VERSION 5.7 ;
  NOWIREEXTENSIONATPIN ON ;
  DIVIDERCHAR "/" ;
  BUSBITCHARS "[]" ;
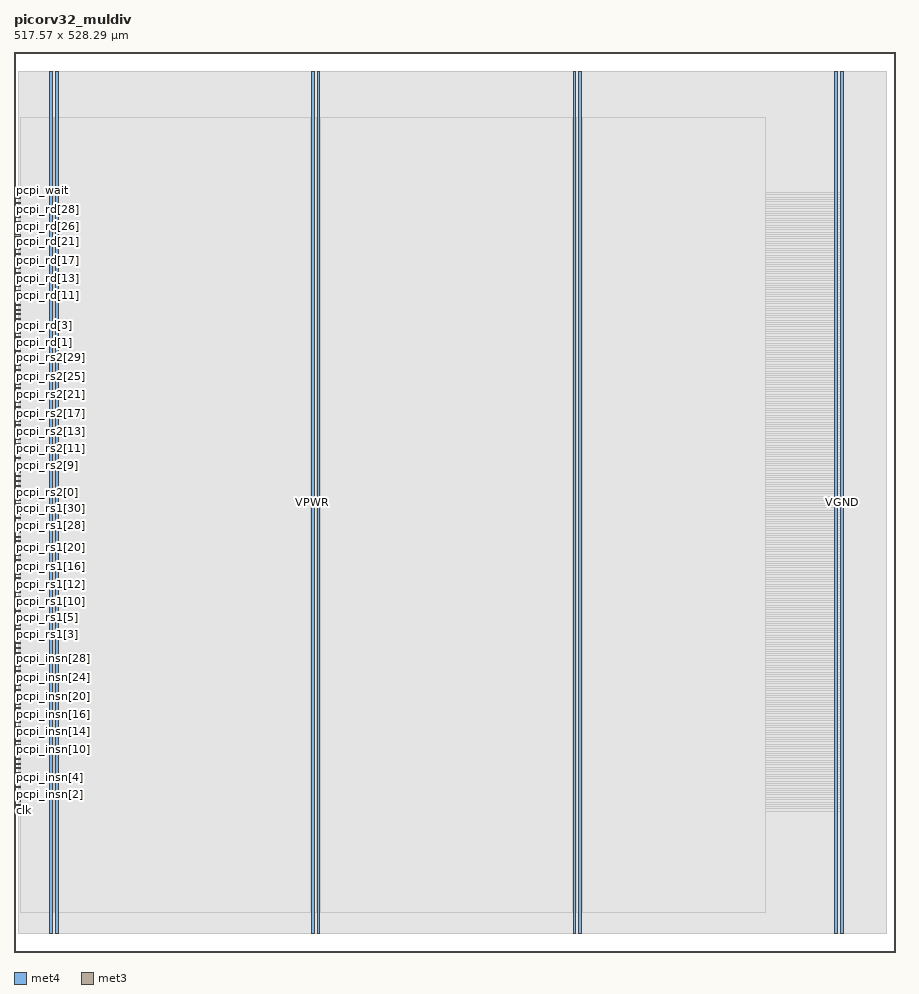
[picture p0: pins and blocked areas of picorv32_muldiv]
MACRO picorv32_muldiv
  CLASS BLOCK ;
  FOREIGN picorv32_muldiv ;
  ORIGIN 0.000 0.000 ;
  SIZE 517.570 BY 528.290 ;
  PIN VGND
    DIRECTION INOUT ;
    USE GROUND ;
    PORT
      LAYER met4 ;
        RECT 24.340 10.640 25.940 517.040 ;
    END
    PORT
      LAYER met4 ;
        RECT 177.940 10.640 179.540 517.040 ;
    END
    PORT
      LAYER met4 ;
        RECT 331.540 10.640 333.140 517.040 ;
    END
    PORT
      LAYER met4 ;
        RECT 485.140 10.640 486.740 517.040 ;
    END
  END VGND
  PIN VPWR
    DIRECTION INOUT ;
    USE POWER ;
    PORT
      LAYER met4 ;
        RECT 21.040 10.640 22.640 517.040 ;
    END
    PORT
      LAYER met4 ;
        RECT 174.640 10.640 176.240 517.040 ;
    END
    PORT
      LAYER met4 ;
        RECT 328.240 10.640 329.840 517.040 ;
    END
    PORT
      LAYER met4 ;
        RECT 481.840 10.640 483.440 517.040 ;
    END
  END VPWR
  PIN clk
    DIRECTION INPUT ;
    USE SIGNAL ;
    ANTENNAGATEAREA 1.286700 ;
    ANTENNADIFFAREA 0.434700 ;
    PORT
      LAYER met3 ;
        RECT 0.000 83.000 4.000 83.600 ;
    END
  END clk
  PIN pcpi_insn[0]
    DIRECTION INPUT ;
    USE SIGNAL ;
    ANTENNAGATEAREA 0.631200 ;
    ANTENNADIFFAREA 0.434700 ;
    PORT
      LAYER met3 ;
        RECT 0.000 91.160 4.000 91.760 ;
    END
  END pcpi_insn[0]
  PIN pcpi_insn[10]
    DIRECTION INPUT ;
    USE SIGNAL ;
    PORT
      LAYER met3 ;
        RECT 0.000 118.360 4.000 118.960 ;
    END
  END pcpi_insn[10]
  PIN pcpi_insn[11]
    DIRECTION INPUT ;
    USE SIGNAL ;
    PORT
      LAYER met3 ;
        RECT 0.000 121.080 4.000 121.680 ;
    END
  END pcpi_insn[11]
  PIN pcpi_insn[12]
    DIRECTION INPUT ;
    USE SIGNAL ;
    ANTENNAGATEAREA 0.560700 ;
    ANTENNADIFFAREA 0.434700 ;
    PORT
      LAYER met3 ;
        RECT 0.000 123.800 4.000 124.400 ;
    END
  END pcpi_insn[12]
  PIN pcpi_insn[13]
    DIRECTION INPUT ;
    USE SIGNAL ;
    ANTENNAGATEAREA 0.560700 ;
    ANTENNADIFFAREA 0.434700 ;
    PORT
      LAYER met3 ;
        RECT 0.000 126.520 4.000 127.120 ;
    END
  END pcpi_insn[13]
  PIN pcpi_insn[14]
    DIRECTION INPUT ;
    USE SIGNAL ;
    ANTENNAGATEAREA 0.560700 ;
    ANTENNADIFFAREA 0.434700 ;
    PORT
      LAYER met3 ;
        RECT 0.000 129.240 4.000 129.840 ;
    END
  END pcpi_insn[14]
  PIN pcpi_insn[15]
    DIRECTION INPUT ;
    USE SIGNAL ;
    PORT
      LAYER met3 ;
        RECT 0.000 131.960 4.000 132.560 ;
    END
  END pcpi_insn[15]
  PIN pcpi_insn[16]
    DIRECTION INPUT ;
    USE SIGNAL ;
    PORT
      LAYER met3 ;
        RECT 0.000 134.680 4.000 135.280 ;
    END
  END pcpi_insn[16]
  PIN pcpi_insn[17]
    DIRECTION INPUT ;
    USE SIGNAL ;
    PORT
      LAYER met3 ;
        RECT 0.000 137.400 4.000 138.000 ;
    END
  END pcpi_insn[17]
  PIN pcpi_insn[18]
    DIRECTION INPUT ;
    USE SIGNAL ;
    PORT
      LAYER met3 ;
        RECT 0.000 140.120 4.000 140.720 ;
    END
  END pcpi_insn[18]
  PIN pcpi_insn[19]
    DIRECTION INPUT ;
    USE SIGNAL ;
    PORT
      LAYER met3 ;
        RECT 0.000 142.840 4.000 143.440 ;
    END
  END pcpi_insn[19]
  PIN pcpi_insn[1]
    DIRECTION INPUT ;
    USE SIGNAL ;
    ANTENNAGATEAREA 0.631200 ;
    ANTENNADIFFAREA 0.434700 ;
    PORT
      LAYER met3 ;
        RECT 0.000 93.880 4.000 94.480 ;
    END
  END pcpi_insn[1]
  PIN pcpi_insn[20]
    DIRECTION INPUT ;
    USE SIGNAL ;
    PORT
      LAYER met3 ;
        RECT 0.000 145.560 4.000 146.160 ;
    END
  END pcpi_insn[20]
  PIN pcpi_insn[21]
    DIRECTION INPUT ;
    USE SIGNAL ;
    PORT
      LAYER met3 ;
        RECT 0.000 148.280 4.000 148.880 ;
    END
  END pcpi_insn[21]
  PIN pcpi_insn[22]
    DIRECTION INPUT ;
    USE SIGNAL ;
    PORT
      LAYER met3 ;
        RECT 0.000 151.000 4.000 151.600 ;
    END
  END pcpi_insn[22]
  PIN pcpi_insn[23]
    DIRECTION INPUT ;
    USE SIGNAL ;
    PORT
      LAYER met3 ;
        RECT 0.000 153.720 4.000 154.320 ;
    END
  END pcpi_insn[23]
  PIN pcpi_insn[24]
    DIRECTION INPUT ;
    USE SIGNAL ;
    PORT
      LAYER met3 ;
        RECT 0.000 156.440 4.000 157.040 ;
    END
  END pcpi_insn[24]
  PIN pcpi_insn[25]
    DIRECTION INPUT ;
    USE SIGNAL ;
    ANTENNAGATEAREA 0.631200 ;
    ANTENNADIFFAREA 0.434700 ;
    PORT
      LAYER met3 ;
        RECT 0.000 159.160 4.000 159.760 ;
    END
  END pcpi_insn[25]
  PIN pcpi_insn[26]
    DIRECTION INPUT ;
    USE SIGNAL ;
    ANTENNAGATEAREA 0.631200 ;
    ANTENNADIFFAREA 0.434700 ;
    PORT
      LAYER met3 ;
        RECT 0.000 161.880 4.000 162.480 ;
    END
  END pcpi_insn[26]
  PIN pcpi_insn[27]
    DIRECTION INPUT ;
    USE SIGNAL ;
    ANTENNAGATEAREA 0.631200 ;
    ANTENNADIFFAREA 0.434700 ;
    PORT
      LAYER met3 ;
        RECT 0.000 164.600 4.000 165.200 ;
    END
  END pcpi_insn[27]
  PIN pcpi_insn[28]
    DIRECTION INPUT ;
    USE SIGNAL ;
    ANTENNAGATEAREA 0.631200 ;
    ANTENNADIFFAREA 0.434700 ;
    PORT
      LAYER met3 ;
        RECT 0.000 167.320 4.000 167.920 ;
    END
  END pcpi_insn[28]
  PIN pcpi_insn[29]
    DIRECTION INPUT ;
    USE SIGNAL ;
    ANTENNAGATEAREA 0.631200 ;
    ANTENNADIFFAREA 0.434700 ;
    PORT
      LAYER met3 ;
        RECT 0.000 170.040 4.000 170.640 ;
    END
  END pcpi_insn[29]
  PIN pcpi_insn[2]
    DIRECTION INPUT ;
    USE SIGNAL ;
    ANTENNAGATEAREA 0.631200 ;
    ANTENNADIFFAREA 0.434700 ;
    PORT
      LAYER met3 ;
        RECT 0.000 96.600 4.000 97.200 ;
    END
  END pcpi_insn[2]
  PIN pcpi_insn[30]
    DIRECTION INPUT ;
    USE SIGNAL ;
    ANTENNAGATEAREA 0.631200 ;
    ANTENNADIFFAREA 0.434700 ;
    PORT
      LAYER met3 ;
        RECT 0.000 172.760 4.000 173.360 ;
    END
  END pcpi_insn[30]
  PIN pcpi_insn[31]
    DIRECTION INPUT ;
    USE SIGNAL ;
    ANTENNAGATEAREA 0.631200 ;
    ANTENNADIFFAREA 0.434700 ;
    PORT
      LAYER met3 ;
        RECT 0.000 175.480 4.000 176.080 ;
    END
  END pcpi_insn[31]
  PIN pcpi_insn[3]
    DIRECTION INPUT ;
    USE SIGNAL ;
    ANTENNAGATEAREA 0.631200 ;
    ANTENNADIFFAREA 0.434700 ;
    PORT
      LAYER met3 ;
        RECT 0.000 99.320 4.000 99.920 ;
    END
  END pcpi_insn[3]
  PIN pcpi_insn[4]
    DIRECTION INPUT ;
    USE SIGNAL ;
    ANTENNAGATEAREA 0.631200 ;
    ANTENNADIFFAREA 0.434700 ;
    PORT
      LAYER met3 ;
        RECT 0.000 102.040 4.000 102.640 ;
    END
  END pcpi_insn[4]
  PIN pcpi_insn[5]
    DIRECTION INPUT ;
    USE SIGNAL ;
    ANTENNAGATEAREA 0.631200 ;
    ANTENNADIFFAREA 0.434700 ;
    PORT
      LAYER met3 ;
        RECT 0.000 104.760 4.000 105.360 ;
    END
  END pcpi_insn[5]
  PIN pcpi_insn[6]
    DIRECTION INPUT ;
    USE SIGNAL ;
    ANTENNAGATEAREA 0.560700 ;
    ANTENNADIFFAREA 0.434700 ;
    PORT
      LAYER met3 ;
        RECT 0.000 107.480 4.000 108.080 ;
    END
  END pcpi_insn[6]
  PIN pcpi_insn[7]
    DIRECTION INPUT ;
    USE SIGNAL ;
    PORT
      LAYER met3 ;
        RECT 0.000 110.200 4.000 110.800 ;
    END
  END pcpi_insn[7]
  PIN pcpi_insn[8]
    DIRECTION INPUT ;
    USE SIGNAL ;
    PORT
      LAYER met3 ;
        RECT 0.000 112.920 4.000 113.520 ;
    END
  END pcpi_insn[8]
  PIN pcpi_insn[9]
    DIRECTION INPUT ;
    USE SIGNAL ;
    PORT
      LAYER met3 ;
        RECT 0.000 115.640 4.000 116.240 ;
    END
  END pcpi_insn[9]
  PIN pcpi_rd[0]
    DIRECTION OUTPUT ;
    USE SIGNAL ;
    ANTENNAGATEAREA 0.434700 ;
    ANTENNADIFFAREA 0.880200 ;
    PORT
      LAYER met3 ;
        RECT 0.000 355.000 4.000 355.600 ;
    END
  END pcpi_rd[0]
  PIN pcpi_rd[10]
    DIRECTION OUTPUT ;
    USE SIGNAL ;
    ANTENNAGATEAREA 0.434700 ;
    ANTENNADIFFAREA 0.880200 ;
    PORT
      LAYER met3 ;
        RECT 0.000 382.200 4.000 382.800 ;
    END
  END pcpi_rd[10]
  PIN pcpi_rd[11]
    DIRECTION OUTPUT ;
    USE SIGNAL ;
    ANTENNAGATEAREA 0.434700 ;
    ANTENNADIFFAREA 0.880200 ;
    PORT
      LAYER met3 ;
        RECT 0.000 384.920 4.000 385.520 ;
    END
  END pcpi_rd[11]
  PIN pcpi_rd[12]
    DIRECTION OUTPUT ;
    USE SIGNAL ;
    ANTENNAGATEAREA 0.434700 ;
    ANTENNADIFFAREA 0.880200 ;
    PORT
      LAYER met3 ;
        RECT 0.000 387.640 4.000 388.240 ;
    END
  END pcpi_rd[12]
  PIN pcpi_rd[13]
    DIRECTION OUTPUT ;
    USE SIGNAL ;
    ANTENNAGATEAREA 0.434700 ;
    ANTENNADIFFAREA 0.880200 ;
    PORT
      LAYER met3 ;
        RECT 0.000 390.360 4.000 390.960 ;
    END
  END pcpi_rd[13]
  PIN pcpi_rd[14]
    DIRECTION OUTPUT ;
    USE SIGNAL ;
    ANTENNAGATEAREA 0.434700 ;
    ANTENNADIFFAREA 0.880200 ;
    PORT
      LAYER met3 ;
        RECT 0.000 393.080 4.000 393.680 ;
    END
  END pcpi_rd[14]
  PIN pcpi_rd[15]
    DIRECTION OUTPUT ;
    USE SIGNAL ;
    ANTENNAGATEAREA 0.434700 ;
    ANTENNADIFFAREA 0.880200 ;
    PORT
      LAYER met3 ;
        RECT 0.000 395.800 4.000 396.400 ;
    END
  END pcpi_rd[15]
  PIN pcpi_rd[16]
    DIRECTION OUTPUT ;
    USE SIGNAL ;
    ANTENNAGATEAREA 0.434700 ;
    ANTENNADIFFAREA 0.880200 ;
    PORT
      LAYER met3 ;
        RECT 0.000 398.520 4.000 399.120 ;
    END
  END pcpi_rd[16]
  PIN pcpi_rd[17]
    DIRECTION OUTPUT ;
    USE SIGNAL ;
    ANTENNAGATEAREA 0.434700 ;
    ANTENNADIFFAREA 0.880200 ;
    PORT
      LAYER met3 ;
        RECT 0.000 401.240 4.000 401.840 ;
    END
  END pcpi_rd[17]
  PIN pcpi_rd[18]
    DIRECTION OUTPUT ;
    USE SIGNAL ;
    ANTENNAGATEAREA 0.434700 ;
    ANTENNADIFFAREA 0.880200 ;
    PORT
      LAYER met3 ;
        RECT 0.000 403.960 4.000 404.560 ;
    END
  END pcpi_rd[18]
  PIN pcpi_rd[19]
    DIRECTION OUTPUT ;
    USE SIGNAL ;
    ANTENNAGATEAREA 0.434700 ;
    ANTENNADIFFAREA 0.880200 ;
    PORT
      LAYER met3 ;
        RECT 0.000 406.680 4.000 407.280 ;
    END
  END pcpi_rd[19]
  PIN pcpi_rd[1]
    DIRECTION OUTPUT ;
    USE SIGNAL ;
    ANTENNAGATEAREA 0.434700 ;
    ANTENNADIFFAREA 0.880200 ;
    PORT
      LAYER met3 ;
        RECT 0.000 357.720 4.000 358.320 ;
    END
  END pcpi_rd[1]
  PIN pcpi_rd[20]
    DIRECTION OUTPUT ;
    USE SIGNAL ;
    ANTENNAGATEAREA 0.434700 ;
    ANTENNADIFFAREA 0.880200 ;
    PORT
      LAYER met3 ;
        RECT 0.000 409.400 4.000 410.000 ;
    END
  END pcpi_rd[20]
  PIN pcpi_rd[21]
    DIRECTION OUTPUT ;
    USE SIGNAL ;
    ANTENNAGATEAREA 0.434700 ;
    ANTENNADIFFAREA 0.880200 ;
    PORT
      LAYER met3 ;
        RECT 0.000 412.120 4.000 412.720 ;
    END
  END pcpi_rd[21]
  PIN pcpi_rd[22]
    DIRECTION OUTPUT ;
    USE SIGNAL ;
    ANTENNAGATEAREA 0.434700 ;
    ANTENNADIFFAREA 0.880200 ;
    PORT
      LAYER met3 ;
        RECT 0.000 414.840 4.000 415.440 ;
    END
  END pcpi_rd[22]
  PIN pcpi_rd[23]
    DIRECTION OUTPUT ;
    USE SIGNAL ;
    ANTENNAGATEAREA 0.434700 ;
    ANTENNADIFFAREA 0.880200 ;
    PORT
      LAYER met3 ;
        RECT 0.000 417.560 4.000 418.160 ;
    END
  END pcpi_rd[23]
  PIN pcpi_rd[24]
    DIRECTION OUTPUT ;
    USE SIGNAL ;
    ANTENNAGATEAREA 0.434700 ;
    ANTENNADIFFAREA 0.880200 ;
    PORT
      LAYER met3 ;
        RECT 0.000 420.280 4.000 420.880 ;
    END
  END pcpi_rd[24]
  PIN pcpi_rd[25]
    DIRECTION OUTPUT ;
    USE SIGNAL ;
    ANTENNAGATEAREA 0.434700 ;
    ANTENNADIFFAREA 0.880200 ;
    PORT
      LAYER met3 ;
        RECT 0.000 423.000 4.000 423.600 ;
    END
  END pcpi_rd[25]
  PIN pcpi_rd[26]
    DIRECTION OUTPUT ;
    USE SIGNAL ;
    ANTENNAGATEAREA 0.434700 ;
    ANTENNADIFFAREA 0.880200 ;
    PORT
      LAYER met3 ;
        RECT 0.000 425.720 4.000 426.320 ;
    END
  END pcpi_rd[26]
  PIN pcpi_rd[27]
    DIRECTION OUTPUT ;
    USE SIGNAL ;
    ANTENNAGATEAREA 0.434700 ;
    ANTENNADIFFAREA 0.880200 ;
    PORT
      LAYER met3 ;
        RECT 0.000 428.440 4.000 429.040 ;
    END
  END pcpi_rd[27]
  PIN pcpi_rd[28]
    DIRECTION OUTPUT ;
    USE SIGNAL ;
    ANTENNAGATEAREA 0.434700 ;
    ANTENNADIFFAREA 0.880200 ;
    PORT
      LAYER met3 ;
        RECT 0.000 431.160 4.000 431.760 ;
    END
  END pcpi_rd[28]
  PIN pcpi_rd[29]
    DIRECTION OUTPUT ;
    USE SIGNAL ;
    ANTENNAGATEAREA 0.434700 ;
    ANTENNADIFFAREA 0.880200 ;
    PORT
      LAYER met3 ;
        RECT 0.000 433.880 4.000 434.480 ;
    END
  END pcpi_rd[29]
  PIN pcpi_rd[2]
    DIRECTION OUTPUT ;
    USE SIGNAL ;
    ANTENNAGATEAREA 0.434700 ;
    ANTENNADIFFAREA 0.880200 ;
    PORT
      LAYER met3 ;
        RECT 0.000 360.440 4.000 361.040 ;
    END
  END pcpi_rd[2]
  PIN pcpi_rd[30]
    DIRECTION OUTPUT ;
    USE SIGNAL ;
    ANTENNAGATEAREA 0.434700 ;
    ANTENNADIFFAREA 0.880200 ;
    PORT
      LAYER met3 ;
        RECT 0.000 436.600 4.000 437.200 ;
    END
  END pcpi_rd[30]
  PIN pcpi_rd[31]
    DIRECTION OUTPUT ;
    USE SIGNAL ;
    ANTENNAGATEAREA 0.434700 ;
    ANTENNADIFFAREA 0.880200 ;
    PORT
      LAYER met3 ;
        RECT 0.000 439.320 4.000 439.920 ;
    END
  END pcpi_rd[31]
  PIN pcpi_rd[3]
    DIRECTION OUTPUT ;
    USE SIGNAL ;
    ANTENNAGATEAREA 0.434700 ;
    ANTENNADIFFAREA 0.880200 ;
    PORT
      LAYER met3 ;
        RECT 0.000 363.160 4.000 363.760 ;
    END
  END pcpi_rd[3]
  PIN pcpi_rd[4]
    DIRECTION OUTPUT ;
    USE SIGNAL ;
    ANTENNAGATEAREA 0.434700 ;
    ANTENNADIFFAREA 0.880200 ;
    PORT
      LAYER met3 ;
        RECT 0.000 365.880 4.000 366.480 ;
    END
  END pcpi_rd[4]
  PIN pcpi_rd[5]
    DIRECTION OUTPUT ;
    USE SIGNAL ;
    ANTENNAGATEAREA 0.434700 ;
    ANTENNADIFFAREA 0.880200 ;
    PORT
      LAYER met3 ;
        RECT 0.000 368.600 4.000 369.200 ;
    END
  END pcpi_rd[5]
  PIN pcpi_rd[6]
    DIRECTION OUTPUT ;
    USE SIGNAL ;
    ANTENNAGATEAREA 0.434700 ;
    ANTENNADIFFAREA 0.880200 ;
    PORT
      LAYER met3 ;
        RECT 0.000 371.320 4.000 371.920 ;
    END
  END pcpi_rd[6]
  PIN pcpi_rd[7]
    DIRECTION OUTPUT ;
    USE SIGNAL ;
    ANTENNAGATEAREA 0.434700 ;
    ANTENNADIFFAREA 0.880200 ;
    PORT
      LAYER met3 ;
        RECT 0.000 374.040 4.000 374.640 ;
    END
  END pcpi_rd[7]
  PIN pcpi_rd[8]
    DIRECTION OUTPUT ;
    USE SIGNAL ;
    ANTENNAGATEAREA 0.434700 ;
    ANTENNADIFFAREA 0.880200 ;
    PORT
      LAYER met3 ;
        RECT 0.000 376.760 4.000 377.360 ;
    END
  END pcpi_rd[8]
  PIN pcpi_rd[9]
    DIRECTION OUTPUT ;
    USE SIGNAL ;
    ANTENNAGATEAREA 0.434700 ;
    ANTENNADIFFAREA 0.880200 ;
    PORT
      LAYER met3 ;
        RECT 0.000 379.480 4.000 380.080 ;
    END
  END pcpi_rd[9]
  PIN pcpi_ready
    DIRECTION OUTPUT ;
    USE SIGNAL ;
    ANTENNAGATEAREA 0.434700 ;
    ANTENNADIFFAREA 0.880200 ;
    PORT
      LAYER met3 ;
        RECT 0.000 444.760 4.000 445.360 ;
    END
  END pcpi_ready
  PIN pcpi_rs1[0]
    DIRECTION INPUT ;
    USE SIGNAL ;
    ANTENNAGATEAREA 0.560700 ;
    ANTENNADIFFAREA 0.434700 ;
    PORT
      LAYER met3 ;
        RECT 0.000 178.200 4.000 178.800 ;
    END
  END pcpi_rs1[0]
  PIN pcpi_rs1[10]
    DIRECTION INPUT ;
    USE SIGNAL ;
    ANTENNAGATEAREA 0.560700 ;
    ANTENNADIFFAREA 0.434700 ;
    PORT
      LAYER met3 ;
        RECT 0.000 205.400 4.000 206.000 ;
    END
  END pcpi_rs1[10]
  PIN pcpi_rs1[11]
    DIRECTION INPUT ;
    USE SIGNAL ;
    ANTENNAGATEAREA 0.560700 ;
    ANTENNADIFFAREA 0.434700 ;
    PORT
      LAYER met3 ;
        RECT 0.000 208.120 4.000 208.720 ;
    END
  END pcpi_rs1[11]
  PIN pcpi_rs1[12]
    DIRECTION INPUT ;
    USE SIGNAL ;
    ANTENNAGATEAREA 0.560700 ;
    ANTENNADIFFAREA 0.434700 ;
    PORT
      LAYER met3 ;
        RECT 0.000 210.840 4.000 211.440 ;
    END
  END pcpi_rs1[12]
  PIN pcpi_rs1[13]
    DIRECTION INPUT ;
    USE SIGNAL ;
    ANTENNAGATEAREA 0.560700 ;
    ANTENNADIFFAREA 0.434700 ;
    PORT
      LAYER met3 ;
        RECT 0.000 213.560 4.000 214.160 ;
    END
  END pcpi_rs1[13]
  PIN pcpi_rs1[14]
    DIRECTION INPUT ;
    USE SIGNAL ;
    ANTENNAGATEAREA 0.560700 ;
    ANTENNADIFFAREA 0.434700 ;
    PORT
      LAYER met3 ;
        RECT 0.000 216.280 4.000 216.880 ;
    END
  END pcpi_rs1[14]
  PIN pcpi_rs1[15]
    DIRECTION INPUT ;
    USE SIGNAL ;
    ANTENNAGATEAREA 0.560700 ;
    ANTENNADIFFAREA 0.434700 ;
    PORT
      LAYER met3 ;
        RECT 0.000 219.000 4.000 219.600 ;
    END
  END pcpi_rs1[15]
  PIN pcpi_rs1[16]
    DIRECTION INPUT ;
    USE SIGNAL ;
    ANTENNAGATEAREA 0.560700 ;
    ANTENNADIFFAREA 0.434700 ;
    PORT
      LAYER met3 ;
        RECT 0.000 221.720 4.000 222.320 ;
    END
  END pcpi_rs1[16]
  PIN pcpi_rs1[17]
    DIRECTION INPUT ;
    USE SIGNAL ;
    ANTENNAGATEAREA 0.560700 ;
    ANTENNADIFFAREA 0.434700 ;
    PORT
      LAYER met3 ;
        RECT 0.000 224.440 4.000 225.040 ;
    END
  END pcpi_rs1[17]
  PIN pcpi_rs1[18]
    DIRECTION INPUT ;
    USE SIGNAL ;
    ANTENNAGATEAREA 0.560700 ;
    ANTENNADIFFAREA 0.434700 ;
    PORT
      LAYER met3 ;
        RECT 0.000 227.160 4.000 227.760 ;
    END
  END pcpi_rs1[18]
  PIN pcpi_rs1[19]
    DIRECTION INPUT ;
    USE SIGNAL ;
    ANTENNAGATEAREA 0.560700 ;
    ANTENNADIFFAREA 0.434700 ;
    PORT
      LAYER met3 ;
        RECT 0.000 229.880 4.000 230.480 ;
    END
  END pcpi_rs1[19]
  PIN pcpi_rs1[1]
    DIRECTION INPUT ;
    USE SIGNAL ;
    ANTENNAGATEAREA 0.560700 ;
    ANTENNADIFFAREA 0.434700 ;
    PORT
      LAYER met3 ;
        RECT 0.000 180.920 4.000 181.520 ;
    END
  END pcpi_rs1[1]
  PIN pcpi_rs1[20]
    DIRECTION INPUT ;
    USE SIGNAL ;
    ANTENNAGATEAREA 0.560700 ;
    ANTENNADIFFAREA 0.434700 ;
    PORT
      LAYER met3 ;
        RECT 0.000 232.600 4.000 233.200 ;
    END
  END pcpi_rs1[20]
  PIN pcpi_rs1[21]
    DIRECTION INPUT ;
    USE SIGNAL ;
    ANTENNAGATEAREA 0.560700 ;
    ANTENNADIFFAREA 0.434700 ;
    PORT
      LAYER met3 ;
        RECT 0.000 235.320 4.000 235.920 ;
    END
  END pcpi_rs1[21]
  PIN pcpi_rs1[22]
    DIRECTION INPUT ;
    USE SIGNAL ;
    ANTENNAGATEAREA 0.560700 ;
    ANTENNADIFFAREA 0.434700 ;
    PORT
      LAYER met3 ;
        RECT 0.000 238.040 4.000 238.640 ;
    END
  END pcpi_rs1[22]
  PIN pcpi_rs1[23]
    DIRECTION INPUT ;
    USE SIGNAL ;
    ANTENNAGATEAREA 0.560700 ;
    ANTENNADIFFAREA 0.434700 ;
    PORT
      LAYER met3 ;
        RECT 0.000 240.760 4.000 241.360 ;
    END
  END pcpi_rs1[23]
  PIN pcpi_rs1[24]
    DIRECTION INPUT ;
    USE SIGNAL ;
    ANTENNAGATEAREA 0.560700 ;
    ANTENNADIFFAREA 0.434700 ;
    PORT
      LAYER met3 ;
        RECT 0.000 243.480 4.000 244.080 ;
    END
  END pcpi_rs1[24]
  PIN pcpi_rs1[25]
    DIRECTION INPUT ;
    USE SIGNAL ;
    ANTENNAGATEAREA 0.560700 ;
    ANTENNADIFFAREA 0.434700 ;
    PORT
      LAYER met3 ;
        RECT 0.000 246.200 4.000 246.800 ;
    END
  END pcpi_rs1[25]
  PIN pcpi_rs1[26]
    DIRECTION INPUT ;
    USE SIGNAL ;
    ANTENNAGATEAREA 0.560700 ;
    ANTENNADIFFAREA 0.434700 ;
    PORT
      LAYER met3 ;
        RECT 0.000 248.920 4.000 249.520 ;
    END
  END pcpi_rs1[26]
  PIN pcpi_rs1[27]
    DIRECTION INPUT ;
    USE SIGNAL ;
    ANTENNAGATEAREA 0.560700 ;
    ANTENNADIFFAREA 0.434700 ;
    PORT
      LAYER met3 ;
        RECT 0.000 251.640 4.000 252.240 ;
    END
  END pcpi_rs1[27]
  PIN pcpi_rs1[28]
    DIRECTION INPUT ;
    USE SIGNAL ;
    ANTENNAGATEAREA 0.560700 ;
    ANTENNADIFFAREA 0.434700 ;
    PORT
      LAYER met3 ;
        RECT 0.000 254.360 4.000 254.960 ;
    END
  END pcpi_rs1[28]
  PIN pcpi_rs1[29]
    DIRECTION INPUT ;
    USE SIGNAL ;
    ANTENNAGATEAREA 0.560700 ;
    ANTENNADIFFAREA 0.434700 ;
    PORT
      LAYER met3 ;
        RECT 0.000 257.080 4.000 257.680 ;
    END
  END pcpi_rs1[29]
  PIN pcpi_rs1[2]
    DIRECTION INPUT ;
    USE SIGNAL ;
    ANTENNAGATEAREA 0.560700 ;
    ANTENNADIFFAREA 0.434700 ;
    PORT
      LAYER met3 ;
        RECT 0.000 183.640 4.000 184.240 ;
    END
  END pcpi_rs1[2]
  PIN pcpi_rs1[30]
    DIRECTION INPUT ;
    USE SIGNAL ;
    ANTENNAGATEAREA 0.560700 ;
    ANTENNADIFFAREA 0.434700 ;
    PORT
      LAYER met3 ;
        RECT 0.000 259.800 4.000 260.400 ;
    END
  END pcpi_rs1[30]
  PIN pcpi_rs1[31]
    DIRECTION INPUT ;
    USE SIGNAL ;
    ANTENNAGATEAREA 0.560700 ;
    ANTENNADIFFAREA 0.434700 ;
    PORT
      LAYER met3 ;
        RECT 0.000 262.520 4.000 263.120 ;
    END
  END pcpi_rs1[31]
  PIN pcpi_rs1[3]
    DIRECTION INPUT ;
    USE SIGNAL ;
    ANTENNAGATEAREA 0.560700 ;
    ANTENNADIFFAREA 0.434700 ;
    PORT
      LAYER met3 ;
        RECT 0.000 186.360 4.000 186.960 ;
    END
  END pcpi_rs1[3]
  PIN pcpi_rs1[4]
    DIRECTION INPUT ;
    USE SIGNAL ;
    ANTENNAGATEAREA 0.560700 ;
    ANTENNADIFFAREA 0.434700 ;
    PORT
      LAYER met3 ;
        RECT 0.000 189.080 4.000 189.680 ;
    END
  END pcpi_rs1[4]
  PIN pcpi_rs1[5]
    DIRECTION INPUT ;
    USE SIGNAL ;
    ANTENNAGATEAREA 0.560700 ;
    ANTENNADIFFAREA 0.434700 ;
    PORT
      LAYER met3 ;
        RECT 0.000 191.800 4.000 192.400 ;
    END
  END pcpi_rs1[5]
  PIN pcpi_rs1[6]
    DIRECTION INPUT ;
    USE SIGNAL ;
    ANTENNAGATEAREA 0.560700 ;
    ANTENNADIFFAREA 0.434700 ;
    PORT
      LAYER met3 ;
        RECT 0.000 194.520 4.000 195.120 ;
    END
  END pcpi_rs1[6]
  PIN pcpi_rs1[7]
    DIRECTION INPUT ;
    USE SIGNAL ;
    ANTENNAGATEAREA 0.560700 ;
    ANTENNADIFFAREA 0.434700 ;
    PORT
      LAYER met3 ;
        RECT 0.000 197.240 4.000 197.840 ;
    END
  END pcpi_rs1[7]
  PIN pcpi_rs1[8]
    DIRECTION INPUT ;
    USE SIGNAL ;
    ANTENNAGATEAREA 0.560700 ;
    ANTENNADIFFAREA 0.434700 ;
    PORT
      LAYER met3 ;
        RECT 0.000 199.960 4.000 200.560 ;
    END
  END pcpi_rs1[8]
  PIN pcpi_rs1[9]
    DIRECTION INPUT ;
    USE SIGNAL ;
    ANTENNAGATEAREA 0.560700 ;
    ANTENNADIFFAREA 0.434700 ;
    PORT
      LAYER met3 ;
        RECT 0.000 202.680 4.000 203.280 ;
    END
  END pcpi_rs1[9]
  PIN pcpi_rs2[0]
    DIRECTION INPUT ;
    USE SIGNAL ;
    ANTENNAGATEAREA 0.560700 ;
    ANTENNADIFFAREA 0.434700 ;
    PORT
      LAYER met3 ;
        RECT 0.000 265.240 4.000 265.840 ;
    END
  END pcpi_rs2[0]
  PIN pcpi_rs2[10]
    DIRECTION INPUT ;
    USE SIGNAL ;
    ANTENNAGATEAREA 0.560700 ;
    ANTENNADIFFAREA 0.434700 ;
    PORT
      LAYER met3 ;
        RECT 0.000 292.440 4.000 293.040 ;
    END
  END pcpi_rs2[10]
  PIN pcpi_rs2[11]
    DIRECTION INPUT ;
    USE SIGNAL ;
    ANTENNAGATEAREA 0.560700 ;
    ANTENNADIFFAREA 0.434700 ;
    PORT
      LAYER met3 ;
        RECT 0.000 295.160 4.000 295.760 ;
    END
  END pcpi_rs2[11]
  PIN pcpi_rs2[12]
    DIRECTION INPUT ;
    USE SIGNAL ;
    ANTENNAGATEAREA 0.560700 ;
    ANTENNADIFFAREA 0.434700 ;
    PORT
      LAYER met3 ;
        RECT 0.000 297.880 4.000 298.480 ;
    END
  END pcpi_rs2[12]
  PIN pcpi_rs2[13]
    DIRECTION INPUT ;
    USE SIGNAL ;
    ANTENNAGATEAREA 0.560700 ;
    ANTENNADIFFAREA 0.434700 ;
    PORT
      LAYER met3 ;
        RECT 0.000 300.600 4.000 301.200 ;
    END
  END pcpi_rs2[13]
  PIN pcpi_rs2[14]
    DIRECTION INPUT ;
    USE SIGNAL ;
    ANTENNAGATEAREA 0.560700 ;
    ANTENNADIFFAREA 0.434700 ;
    PORT
      LAYER met3 ;
        RECT 0.000 303.320 4.000 303.920 ;
    END
  END pcpi_rs2[14]
  PIN pcpi_rs2[15]
    DIRECTION INPUT ;
    USE SIGNAL ;
    ANTENNAGATEAREA 0.560700 ;
    ANTENNADIFFAREA 0.434700 ;
    PORT
      LAYER met3 ;
        RECT 0.000 306.040 4.000 306.640 ;
    END
  END pcpi_rs2[15]
  PIN pcpi_rs2[16]
    DIRECTION INPUT ;
    USE SIGNAL ;
    ANTENNAGATEAREA 0.560700 ;
    ANTENNADIFFAREA 0.434700 ;
    PORT
      LAYER met3 ;
        RECT 0.000 308.760 4.000 309.360 ;
    END
  END pcpi_rs2[16]
  PIN pcpi_rs2[17]
    DIRECTION INPUT ;
    USE SIGNAL ;
    ANTENNAGATEAREA 0.560700 ;
    ANTENNADIFFAREA 0.434700 ;
    PORT
      LAYER met3 ;
        RECT 0.000 311.480 4.000 312.080 ;
    END
  END pcpi_rs2[17]
  PIN pcpi_rs2[18]
    DIRECTION INPUT ;
    USE SIGNAL ;
    ANTENNAGATEAREA 0.560700 ;
    ANTENNADIFFAREA 0.434700 ;
    PORT
      LAYER met3 ;
        RECT 0.000 314.200 4.000 314.800 ;
    END
  END pcpi_rs2[18]
  PIN pcpi_rs2[19]
    DIRECTION INPUT ;
    USE SIGNAL ;
    ANTENNAGATEAREA 0.560700 ;
    ANTENNADIFFAREA 0.434700 ;
    PORT
      LAYER met3 ;
        RECT 0.000 316.920 4.000 317.520 ;
    END
  END pcpi_rs2[19]
  PIN pcpi_rs2[1]
    DIRECTION INPUT ;
    USE SIGNAL ;
    ANTENNAGATEAREA 0.560700 ;
    ANTENNADIFFAREA 0.434700 ;
    PORT
      LAYER met3 ;
        RECT 0.000 267.960 4.000 268.560 ;
    END
  END pcpi_rs2[1]
  PIN pcpi_rs2[20]
    DIRECTION INPUT ;
    USE SIGNAL ;
    ANTENNAGATEAREA 0.560700 ;
    ANTENNADIFFAREA 0.434700 ;
    PORT
      LAYER met3 ;
        RECT 0.000 319.640 4.000 320.240 ;
    END
  END pcpi_rs2[20]
  PIN pcpi_rs2[21]
    DIRECTION INPUT ;
    USE SIGNAL ;
    ANTENNAGATEAREA 0.560700 ;
    ANTENNADIFFAREA 0.434700 ;
    PORT
      LAYER met3 ;
        RECT 0.000 322.360 4.000 322.960 ;
    END
  END pcpi_rs2[21]
  PIN pcpi_rs2[22]
    DIRECTION INPUT ;
    USE SIGNAL ;
    ANTENNAGATEAREA 0.560700 ;
    ANTENNADIFFAREA 0.434700 ;
    PORT
      LAYER met3 ;
        RECT 0.000 325.080 4.000 325.680 ;
    END
  END pcpi_rs2[22]
  PIN pcpi_rs2[23]
    DIRECTION INPUT ;
    USE SIGNAL ;
    ANTENNAGATEAREA 0.560700 ;
    ANTENNADIFFAREA 0.434700 ;
    PORT
      LAYER met3 ;
        RECT 0.000 327.800 4.000 328.400 ;
    END
  END pcpi_rs2[23]
  PIN pcpi_rs2[24]
    DIRECTION INPUT ;
    USE SIGNAL ;
    ANTENNAGATEAREA 0.560700 ;
    ANTENNADIFFAREA 0.434700 ;
    PORT
      LAYER met3 ;
        RECT 0.000 330.520 4.000 331.120 ;
    END
  END pcpi_rs2[24]
  PIN pcpi_rs2[25]
    DIRECTION INPUT ;
    USE SIGNAL ;
    ANTENNAGATEAREA 0.560700 ;
    ANTENNADIFFAREA 0.434700 ;
    PORT
      LAYER met3 ;
        RECT 0.000 333.240 4.000 333.840 ;
    END
  END pcpi_rs2[25]
  PIN pcpi_rs2[26]
    DIRECTION INPUT ;
    USE SIGNAL ;
    ANTENNAGATEAREA 0.560700 ;
    ANTENNADIFFAREA 0.434700 ;
    PORT
      LAYER met3 ;
        RECT 0.000 335.960 4.000 336.560 ;
    END
  END pcpi_rs2[26]
  PIN pcpi_rs2[27]
    DIRECTION INPUT ;
    USE SIGNAL ;
    ANTENNAGATEAREA 0.560700 ;
    ANTENNADIFFAREA 0.434700 ;
    PORT
      LAYER met3 ;
        RECT 0.000 338.680 4.000 339.280 ;
    END
  END pcpi_rs2[27]
  PIN pcpi_rs2[28]
    DIRECTION INPUT ;
    USE SIGNAL ;
    ANTENNAGATEAREA 0.560700 ;
    ANTENNADIFFAREA 0.434700 ;
    PORT
      LAYER met3 ;
        RECT 0.000 341.400 4.000 342.000 ;
    END
  END pcpi_rs2[28]
  PIN pcpi_rs2[29]
    DIRECTION INPUT ;
    USE SIGNAL ;
    ANTENNAGATEAREA 0.560700 ;
    ANTENNADIFFAREA 0.434700 ;
    PORT
      LAYER met3 ;
        RECT 0.000 344.120 4.000 344.720 ;
    END
  END pcpi_rs2[29]
  PIN pcpi_rs2[2]
    DIRECTION INPUT ;
    USE SIGNAL ;
    ANTENNAGATEAREA 0.560700 ;
    ANTENNADIFFAREA 0.434700 ;
    PORT
      LAYER met3 ;
        RECT 0.000 270.680 4.000 271.280 ;
    END
  END pcpi_rs2[2]
  PIN pcpi_rs2[30]
    DIRECTION INPUT ;
    USE SIGNAL ;
    ANTENNAGATEAREA 0.560700 ;
    ANTENNADIFFAREA 0.434700 ;
    PORT
      LAYER met3 ;
        RECT 0.000 346.840 4.000 347.440 ;
    END
  END pcpi_rs2[30]
  PIN pcpi_rs2[31]
    DIRECTION INPUT ;
    USE SIGNAL ;
    ANTENNAGATEAREA 0.560700 ;
    ANTENNADIFFAREA 0.434700 ;
    PORT
      LAYER met3 ;
        RECT 0.000 349.560 4.000 350.160 ;
    END
  END pcpi_rs2[31]
  PIN pcpi_rs2[3]
    DIRECTION INPUT ;
    USE SIGNAL ;
    ANTENNAGATEAREA 0.560700 ;
    ANTENNADIFFAREA 0.434700 ;
    PORT
      LAYER met3 ;
        RECT 0.000 273.400 4.000 274.000 ;
    END
  END pcpi_rs2[3]
  PIN pcpi_rs2[4]
    DIRECTION INPUT ;
    USE SIGNAL ;
    ANTENNAGATEAREA 0.560700 ;
    ANTENNADIFFAREA 0.434700 ;
    PORT
      LAYER met3 ;
        RECT 0.000 276.120 4.000 276.720 ;
    END
  END pcpi_rs2[4]
  PIN pcpi_rs2[5]
    DIRECTION INPUT ;
    USE SIGNAL ;
    ANTENNAGATEAREA 0.560700 ;
    ANTENNADIFFAREA 0.434700 ;
    PORT
      LAYER met3 ;
        RECT 0.000 278.840 4.000 279.440 ;
    END
  END pcpi_rs2[5]
  PIN pcpi_rs2[6]
    DIRECTION INPUT ;
    USE SIGNAL ;
    ANTENNAGATEAREA 0.560700 ;
    ANTENNADIFFAREA 0.434700 ;
    PORT
      LAYER met3 ;
        RECT 0.000 281.560 4.000 282.160 ;
    END
  END pcpi_rs2[6]
  PIN pcpi_rs2[7]
    DIRECTION INPUT ;
    USE SIGNAL ;
    ANTENNAGATEAREA 0.560700 ;
    ANTENNADIFFAREA 0.434700 ;
    PORT
      LAYER met3 ;
        RECT 0.000 284.280 4.000 284.880 ;
    END
  END pcpi_rs2[7]
  PIN pcpi_rs2[8]
    DIRECTION INPUT ;
    USE SIGNAL ;
    ANTENNAGATEAREA 0.560700 ;
    ANTENNADIFFAREA 0.434700 ;
    PORT
      LAYER met3 ;
        RECT 0.000 287.000 4.000 287.600 ;
    END
  END pcpi_rs2[8]
  PIN pcpi_rs2[9]
    DIRECTION INPUT ;
    USE SIGNAL ;
    ANTENNAGATEAREA 0.560700 ;
    ANTENNADIFFAREA 0.434700 ;
    PORT
      LAYER met3 ;
        RECT 0.000 289.720 4.000 290.320 ;
    END
  END pcpi_rs2[9]
  PIN pcpi_valid
    DIRECTION INPUT ;
    USE SIGNAL ;
    ANTENNAGATEAREA 0.631200 ;
    ANTENNADIFFAREA 0.434700 ;
    PORT
      LAYER met3 ;
        RECT 0.000 88.440 4.000 89.040 ;
    END
  END pcpi_valid
  PIN pcpi_wait
    DIRECTION OUTPUT ;
    USE SIGNAL ;
    ANTENNAGATEAREA 0.434700 ;
    ANTENNADIFFAREA 0.880200 ;
    PORT
      LAYER met3 ;
        RECT 0.000 442.040 4.000 442.640 ;
    END
  END pcpi_wait
  PIN pcpi_wr
    DIRECTION OUTPUT ;
    USE SIGNAL ;
    ANTENNAGATEAREA 0.434700 ;
    ANTENNADIFFAREA 0.880200 ;
    PORT
      LAYER met3 ;
        RECT 0.000 352.280 4.000 352.880 ;
    END
  END pcpi_wr
  PIN resetn
    DIRECTION INPUT ;
    USE SIGNAL ;
    ANTENNAGATEAREA 0.560700 ;
    ANTENNADIFFAREA 0.434700 ;
    PORT
      LAYER met3 ;
        RECT 0.000 85.720 4.000 86.320 ;
    END
  END resetn
  OBS
      LAYER nwell ;
        RECT 5.330 10.795 512.170 516.885 ;
      LAYER li1 ;
        RECT 5.520 10.795 511.980 516.885 ;
      LAYER met1 ;
        RECT 2.830 10.640 511.980 517.040 ;
      LAYER met2 ;
        RECT 2.850 10.695 486.710 516.985 ;
      LAYER met3 ;
        RECT 2.825 445.760 486.730 516.965 ;
        RECT 4.400 444.360 486.730 445.760 ;
        RECT 2.825 443.040 486.730 444.360 ;
        RECT 4.400 441.640 486.730 443.040 ;
        RECT 2.825 440.320 486.730 441.640 ;
        RECT 4.400 438.920 486.730 440.320 ;
        RECT 2.825 437.600 486.730 438.920 ;
        RECT 4.400 436.200 486.730 437.600 ;
        RECT 2.825 434.880 486.730 436.200 ;
        RECT 4.400 433.480 486.730 434.880 ;
        RECT 2.825 432.160 486.730 433.480 ;
        RECT 4.400 430.760 486.730 432.160 ;
        RECT 2.825 429.440 486.730 430.760 ;
        RECT 4.400 428.040 486.730 429.440 ;
        RECT 2.825 426.720 486.730 428.040 ;
        RECT 4.400 425.320 486.730 426.720 ;
        RECT 2.825 424.000 486.730 425.320 ;
        RECT 4.400 422.600 486.730 424.000 ;
        RECT 2.825 421.280 486.730 422.600 ;
        RECT 4.400 419.880 486.730 421.280 ;
        RECT 2.825 418.560 486.730 419.880 ;
        RECT 4.400 417.160 486.730 418.560 ;
        RECT 2.825 415.840 486.730 417.160 ;
        RECT 4.400 414.440 486.730 415.840 ;
        RECT 2.825 413.120 486.730 414.440 ;
        RECT 4.400 411.720 486.730 413.120 ;
        RECT 2.825 410.400 486.730 411.720 ;
        RECT 4.400 409.000 486.730 410.400 ;
        RECT 2.825 407.680 486.730 409.000 ;
        RECT 4.400 406.280 486.730 407.680 ;
        RECT 2.825 404.960 486.730 406.280 ;
        RECT 4.400 403.560 486.730 404.960 ;
        RECT 2.825 402.240 486.730 403.560 ;
        RECT 4.400 400.840 486.730 402.240 ;
        RECT 2.825 399.520 486.730 400.840 ;
        RECT 4.400 398.120 486.730 399.520 ;
        RECT 2.825 396.800 486.730 398.120 ;
        RECT 4.400 395.400 486.730 396.800 ;
        RECT 2.825 394.080 486.730 395.400 ;
        RECT 4.400 392.680 486.730 394.080 ;
        RECT 2.825 391.360 486.730 392.680 ;
        RECT 4.400 389.960 486.730 391.360 ;
        RECT 2.825 388.640 486.730 389.960 ;
        RECT 4.400 387.240 486.730 388.640 ;
        RECT 2.825 385.920 486.730 387.240 ;
        RECT 4.400 384.520 486.730 385.920 ;
        RECT 2.825 383.200 486.730 384.520 ;
        RECT 4.400 381.800 486.730 383.200 ;
        RECT 2.825 380.480 486.730 381.800 ;
        RECT 4.400 379.080 486.730 380.480 ;
        RECT 2.825 377.760 486.730 379.080 ;
        RECT 4.400 376.360 486.730 377.760 ;
        RECT 2.825 375.040 486.730 376.360 ;
        RECT 4.400 373.640 486.730 375.040 ;
        RECT 2.825 372.320 486.730 373.640 ;
        RECT 4.400 370.920 486.730 372.320 ;
        RECT 2.825 369.600 486.730 370.920 ;
        RECT 4.400 368.200 486.730 369.600 ;
        RECT 2.825 366.880 486.730 368.200 ;
        RECT 4.400 365.480 486.730 366.880 ;
        RECT 2.825 364.160 486.730 365.480 ;
        RECT 4.400 362.760 486.730 364.160 ;
        RECT 2.825 361.440 486.730 362.760 ;
        RECT 4.400 360.040 486.730 361.440 ;
        RECT 2.825 358.720 486.730 360.040 ;
        RECT 4.400 357.320 486.730 358.720 ;
        RECT 2.825 356.000 486.730 357.320 ;
        RECT 4.400 354.600 486.730 356.000 ;
        RECT 2.825 353.280 486.730 354.600 ;
        RECT 4.400 351.880 486.730 353.280 ;
        RECT 2.825 350.560 486.730 351.880 ;
        RECT 4.400 349.160 486.730 350.560 ;
        RECT 2.825 347.840 486.730 349.160 ;
        RECT 4.400 346.440 486.730 347.840 ;
        RECT 2.825 345.120 486.730 346.440 ;
        RECT 4.400 343.720 486.730 345.120 ;
        RECT 2.825 342.400 486.730 343.720 ;
        RECT 4.400 341.000 486.730 342.400 ;
        RECT 2.825 339.680 486.730 341.000 ;
        RECT 4.400 338.280 486.730 339.680 ;
        RECT 2.825 336.960 486.730 338.280 ;
        RECT 4.400 335.560 486.730 336.960 ;
        RECT 2.825 334.240 486.730 335.560 ;
        RECT 4.400 332.840 486.730 334.240 ;
        RECT 2.825 331.520 486.730 332.840 ;
        RECT 4.400 330.120 486.730 331.520 ;
        RECT 2.825 328.800 486.730 330.120 ;
        RECT 4.400 327.400 486.730 328.800 ;
        RECT 2.825 326.080 486.730 327.400 ;
        RECT 4.400 324.680 486.730 326.080 ;
        RECT 2.825 323.360 486.730 324.680 ;
        RECT 4.400 321.960 486.730 323.360 ;
        RECT 2.825 320.640 486.730 321.960 ;
        RECT 4.400 319.240 486.730 320.640 ;
        RECT 2.825 317.920 486.730 319.240 ;
        RECT 4.400 316.520 486.730 317.920 ;
        RECT 2.825 315.200 486.730 316.520 ;
        RECT 4.400 313.800 486.730 315.200 ;
        RECT 2.825 312.480 486.730 313.800 ;
        RECT 4.400 311.080 486.730 312.480 ;
        RECT 2.825 309.760 486.730 311.080 ;
        RECT 4.400 308.360 486.730 309.760 ;
        RECT 2.825 307.040 486.730 308.360 ;
        RECT 4.400 305.640 486.730 307.040 ;
        RECT 2.825 304.320 486.730 305.640 ;
        RECT 4.400 302.920 486.730 304.320 ;
        RECT 2.825 301.600 486.730 302.920 ;
        RECT 4.400 300.200 486.730 301.600 ;
        RECT 2.825 298.880 486.730 300.200 ;
        RECT 4.400 297.480 486.730 298.880 ;
        RECT 2.825 296.160 486.730 297.480 ;
        RECT 4.400 294.760 486.730 296.160 ;
        RECT 2.825 293.440 486.730 294.760 ;
        RECT 4.400 292.040 486.730 293.440 ;
        RECT 2.825 290.720 486.730 292.040 ;
        RECT 4.400 289.320 486.730 290.720 ;
        RECT 2.825 288.000 486.730 289.320 ;
        RECT 4.400 286.600 486.730 288.000 ;
        RECT 2.825 285.280 486.730 286.600 ;
        RECT 4.400 283.880 486.730 285.280 ;
        RECT 2.825 282.560 486.730 283.880 ;
        RECT 4.400 281.160 486.730 282.560 ;
        RECT 2.825 279.840 486.730 281.160 ;
        RECT 4.400 278.440 486.730 279.840 ;
        RECT 2.825 277.120 486.730 278.440 ;
        RECT 4.400 275.720 486.730 277.120 ;
        RECT 2.825 274.400 486.730 275.720 ;
        RECT 4.400 273.000 486.730 274.400 ;
        RECT 2.825 271.680 486.730 273.000 ;
        RECT 4.400 270.280 486.730 271.680 ;
        RECT 2.825 268.960 486.730 270.280 ;
        RECT 4.400 267.560 486.730 268.960 ;
        RECT 2.825 266.240 486.730 267.560 ;
        RECT 4.400 264.840 486.730 266.240 ;
        RECT 2.825 263.520 486.730 264.840 ;
        RECT 4.400 262.120 486.730 263.520 ;
        RECT 2.825 260.800 486.730 262.120 ;
        RECT 4.400 259.400 486.730 260.800 ;
        RECT 2.825 258.080 486.730 259.400 ;
        RECT 4.400 256.680 486.730 258.080 ;
        RECT 2.825 255.360 486.730 256.680 ;
        RECT 4.400 253.960 486.730 255.360 ;
        RECT 2.825 252.640 486.730 253.960 ;
        RECT 4.400 251.240 486.730 252.640 ;
        RECT 2.825 249.920 486.730 251.240 ;
        RECT 4.400 248.520 486.730 249.920 ;
        RECT 2.825 247.200 486.730 248.520 ;
        RECT 4.400 245.800 486.730 247.200 ;
        RECT 2.825 244.480 486.730 245.800 ;
        RECT 4.400 243.080 486.730 244.480 ;
        RECT 2.825 241.760 486.730 243.080 ;
        RECT 4.400 240.360 486.730 241.760 ;
        RECT 2.825 239.040 486.730 240.360 ;
        RECT 4.400 237.640 486.730 239.040 ;
        RECT 2.825 236.320 486.730 237.640 ;
        RECT 4.400 234.920 486.730 236.320 ;
        RECT 2.825 233.600 486.730 234.920 ;
        RECT 4.400 232.200 486.730 233.600 ;
        RECT 2.825 230.880 486.730 232.200 ;
        RECT 4.400 229.480 486.730 230.880 ;
        RECT 2.825 228.160 486.730 229.480 ;
        RECT 4.400 226.760 486.730 228.160 ;
        RECT 2.825 225.440 486.730 226.760 ;
        RECT 4.400 224.040 486.730 225.440 ;
        RECT 2.825 222.720 486.730 224.040 ;
        RECT 4.400 221.320 486.730 222.720 ;
        RECT 2.825 220.000 486.730 221.320 ;
        RECT 4.400 218.600 486.730 220.000 ;
        RECT 2.825 217.280 486.730 218.600 ;
        RECT 4.400 215.880 486.730 217.280 ;
        RECT 2.825 214.560 486.730 215.880 ;
        RECT 4.400 213.160 486.730 214.560 ;
        RECT 2.825 211.840 486.730 213.160 ;
        RECT 4.400 210.440 486.730 211.840 ;
        RECT 2.825 209.120 486.730 210.440 ;
        RECT 4.400 207.720 486.730 209.120 ;
        RECT 2.825 206.400 486.730 207.720 ;
        RECT 4.400 205.000 486.730 206.400 ;
        RECT 2.825 203.680 486.730 205.000 ;
        RECT 4.400 202.280 486.730 203.680 ;
        RECT 2.825 200.960 486.730 202.280 ;
        RECT 4.400 199.560 486.730 200.960 ;
        RECT 2.825 198.240 486.730 199.560 ;
        RECT 4.400 196.840 486.730 198.240 ;
        RECT 2.825 195.520 486.730 196.840 ;
        RECT 4.400 194.120 486.730 195.520 ;
        RECT 2.825 192.800 486.730 194.120 ;
        RECT 4.400 191.400 486.730 192.800 ;
        RECT 2.825 190.080 486.730 191.400 ;
        RECT 4.400 188.680 486.730 190.080 ;
        RECT 2.825 187.360 486.730 188.680 ;
        RECT 4.400 185.960 486.730 187.360 ;
        RECT 2.825 184.640 486.730 185.960 ;
        RECT 4.400 183.240 486.730 184.640 ;
        RECT 2.825 181.920 486.730 183.240 ;
        RECT 4.400 180.520 486.730 181.920 ;
        RECT 2.825 179.200 486.730 180.520 ;
        RECT 4.400 177.800 486.730 179.200 ;
        RECT 2.825 176.480 486.730 177.800 ;
        RECT 4.400 175.080 486.730 176.480 ;
        RECT 2.825 173.760 486.730 175.080 ;
        RECT 4.400 172.360 486.730 173.760 ;
        RECT 2.825 171.040 486.730 172.360 ;
        RECT 4.400 169.640 486.730 171.040 ;
        RECT 2.825 168.320 486.730 169.640 ;
        RECT 4.400 166.920 486.730 168.320 ;
        RECT 2.825 165.600 486.730 166.920 ;
        RECT 4.400 164.200 486.730 165.600 ;
        RECT 2.825 162.880 486.730 164.200 ;
        RECT 4.400 161.480 486.730 162.880 ;
        RECT 2.825 160.160 486.730 161.480 ;
        RECT 4.400 158.760 486.730 160.160 ;
        RECT 2.825 157.440 486.730 158.760 ;
        RECT 4.400 156.040 486.730 157.440 ;
        RECT 2.825 154.720 486.730 156.040 ;
        RECT 4.400 153.320 486.730 154.720 ;
        RECT 2.825 152.000 486.730 153.320 ;
        RECT 4.400 150.600 486.730 152.000 ;
        RECT 2.825 149.280 486.730 150.600 ;
        RECT 4.400 147.880 486.730 149.280 ;
        RECT 2.825 146.560 486.730 147.880 ;
        RECT 4.400 145.160 486.730 146.560 ;
        RECT 2.825 143.840 486.730 145.160 ;
        RECT 4.400 142.440 486.730 143.840 ;
        RECT 2.825 141.120 486.730 142.440 ;
        RECT 4.400 139.720 486.730 141.120 ;
        RECT 2.825 138.400 486.730 139.720 ;
        RECT 4.400 137.000 486.730 138.400 ;
        RECT 2.825 135.680 486.730 137.000 ;
        RECT 4.400 134.280 486.730 135.680 ;
        RECT 2.825 132.960 486.730 134.280 ;
        RECT 4.400 131.560 486.730 132.960 ;
        RECT 2.825 130.240 486.730 131.560 ;
        RECT 4.400 128.840 486.730 130.240 ;
        RECT 2.825 127.520 486.730 128.840 ;
        RECT 4.400 126.120 486.730 127.520 ;
        RECT 2.825 124.800 486.730 126.120 ;
        RECT 4.400 123.400 486.730 124.800 ;
        RECT 2.825 122.080 486.730 123.400 ;
        RECT 4.400 120.680 486.730 122.080 ;
        RECT 2.825 119.360 486.730 120.680 ;
        RECT 4.400 117.960 486.730 119.360 ;
        RECT 2.825 116.640 486.730 117.960 ;
        RECT 4.400 115.240 486.730 116.640 ;
        RECT 2.825 113.920 486.730 115.240 ;
        RECT 4.400 112.520 486.730 113.920 ;
        RECT 2.825 111.200 486.730 112.520 ;
        RECT 4.400 109.800 486.730 111.200 ;
        RECT 2.825 108.480 486.730 109.800 ;
        RECT 4.400 107.080 486.730 108.480 ;
        RECT 2.825 105.760 486.730 107.080 ;
        RECT 4.400 104.360 486.730 105.760 ;
        RECT 2.825 103.040 486.730 104.360 ;
        RECT 4.400 101.640 486.730 103.040 ;
        RECT 2.825 100.320 486.730 101.640 ;
        RECT 4.400 98.920 486.730 100.320 ;
        RECT 2.825 97.600 486.730 98.920 ;
        RECT 4.400 96.200 486.730 97.600 ;
        RECT 2.825 94.880 486.730 96.200 ;
        RECT 4.400 93.480 486.730 94.880 ;
        RECT 2.825 92.160 486.730 93.480 ;
        RECT 4.400 90.760 486.730 92.160 ;
        RECT 2.825 89.440 486.730 90.760 ;
        RECT 4.400 88.040 486.730 89.440 ;
        RECT 2.825 86.720 486.730 88.040 ;
        RECT 4.400 85.320 486.730 86.720 ;
        RECT 2.825 84.000 486.730 85.320 ;
        RECT 4.400 82.600 486.730 84.000 ;
        RECT 2.825 10.715 486.730 82.600 ;
      LAYER met4 ;
        RECT 3.975 23.295 20.640 490.105 ;
        RECT 23.040 23.295 23.940 490.105 ;
        RECT 26.340 23.295 174.240 490.105 ;
        RECT 176.640 23.295 177.540 490.105 ;
        RECT 179.940 23.295 327.840 490.105 ;
        RECT 330.240 23.295 331.140 490.105 ;
        RECT 333.540 23.295 441.305 490.105 ;
  END
END picorv32_muldiv
END LIBRARY

